VERSION 5.7 ;
  NOWIREEXTENSIONATPIN ON ;
  DIVIDERCHAR "/" ;
  BUSBITCHARS "[]" ;
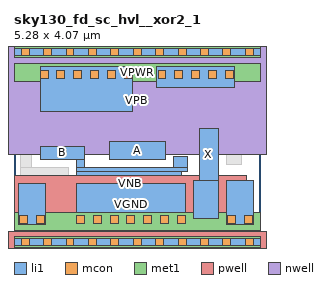
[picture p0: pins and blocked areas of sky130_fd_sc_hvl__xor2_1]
MACRO sky130_fd_sc_hvl__xor2_1
  CLASS BLOCK ;
  FOREIGN sky130_fd_sc_hvl__xor2_1 ;
  ORIGIN 0.000 0.000 ;
  SIZE 5.280 BY 4.070 ;
  PIN A
    ANTENNAGATEAREA 2.250000 ;
    PORT
      LAYER li1 ;
        RECT 2.045 1.775 3.235 2.150 ;
    END
  END A
  PIN B
    ANTENNAGATEAREA 2.250000 ;
    PORT
      LAYER li1 ;
        RECT 0.560 1.775 1.510 2.055 ;
        RECT 1.340 1.595 1.510 1.775 ;
        RECT 3.415 1.595 3.715 1.835 ;
        RECT 1.340 1.505 3.715 1.595 ;
        RECT 1.340 1.425 3.585 1.505 ;
    END
  END B
  PIN VGND
    USE GROUND ;
    PORT
      LAYER li1 ;
        RECT 0.090 0.365 0.680 1.245 ;
        RECT 1.340 0.365 3.670 1.245 ;
        RECT 4.550 0.365 5.140 1.325 ;
      LAYER mcon ;
        RECT 0.120 0.395 0.290 0.565 ;
        RECT 0.480 0.395 0.650 0.565 ;
        RECT 1.340 0.395 1.510 0.565 ;
        RECT 1.700 0.395 1.870 0.565 ;
        RECT 2.060 0.395 2.230 0.565 ;
        RECT 2.420 0.395 2.590 0.565 ;
        RECT 2.780 0.395 2.950 0.565 ;
        RECT 3.140 0.395 3.310 0.565 ;
        RECT 3.500 0.395 3.670 0.565 ;
        RECT 4.580 0.395 4.750 0.565 ;
        RECT 4.940 0.395 5.110 0.565 ;
      LAYER met1 ;
        RECT 0.000 0.255 5.280 0.625 ;
    END
  END VGND
  PIN VNB
    ANTENNADIFFAREA 0.897600 ;
    PORT
      LAYER pwell ;
        RECT 0.020 0.215 4.990 1.415 ;
        RECT -0.130 -0.215 5.410 0.215 ;
      LAYER li1 ;
        RECT 0.000 -0.085 5.280 0.085 ;
      LAYER mcon ;
        RECT 0.155 -0.085 0.325 0.085 ;
        RECT 0.635 -0.085 0.805 0.085 ;
        RECT 1.115 -0.085 1.285 0.085 ;
        RECT 1.595 -0.085 1.765 0.085 ;
        RECT 2.075 -0.085 2.245 0.085 ;
        RECT 2.555 -0.085 2.725 0.085 ;
        RECT 3.035 -0.085 3.205 0.085 ;
        RECT 3.515 -0.085 3.685 0.085 ;
        RECT 3.995 -0.085 4.165 0.085 ;
        RECT 4.475 -0.085 4.645 0.085 ;
        RECT 4.955 -0.085 5.125 0.085 ;
      LAYER met1 ;
        RECT 0.000 -0.115 5.280 0.115 ;
    END
  END VNB
  PIN VPB
    ANTENNADIFFAREA 0.897600 ;
    PORT
      LAYER nwell ;
        RECT -0.330 1.885 5.610 4.485 ;
      LAYER li1 ;
        RECT 0.000 3.985 5.280 4.155 ;
      LAYER mcon ;
        RECT 0.155 3.985 0.325 4.155 ;
        RECT 0.635 3.985 0.805 4.155 ;
        RECT 1.115 3.985 1.285 4.155 ;
        RECT 1.595 3.985 1.765 4.155 ;
        RECT 2.075 3.985 2.245 4.155 ;
        RECT 2.555 3.985 2.725 4.155 ;
        RECT 3.035 3.985 3.205 4.155 ;
        RECT 3.515 3.985 3.685 4.155 ;
        RECT 3.995 3.985 4.165 4.155 ;
        RECT 4.475 3.985 4.645 4.155 ;
        RECT 4.955 3.985 5.125 4.155 ;
      LAYER met1 ;
        RECT 0.000 3.955 5.280 4.185 ;
    END
  END VPB
  PIN VPWR
    USE POWER ;
    PORT
      LAYER li1 ;
        RECT 0.560 2.785 2.530 3.755 ;
        RECT 3.060 3.305 4.720 3.755 ;
      LAYER mcon ;
        RECT 0.560 3.505 0.730 3.675 ;
        RECT 0.920 3.505 1.090 3.675 ;
        RECT 1.280 3.505 1.450 3.675 ;
        RECT 1.640 3.505 1.810 3.675 ;
        RECT 2.000 3.505 2.170 3.675 ;
        RECT 2.360 3.505 2.530 3.675 ;
        RECT 3.085 3.505 3.255 3.675 ;
        RECT 3.445 3.505 3.615 3.675 ;
        RECT 3.805 3.505 3.975 3.675 ;
        RECT 4.165 3.505 4.335 3.675 ;
        RECT 4.525 3.505 4.695 3.675 ;
      LAYER met1 ;
        RECT 0.000 3.445 5.280 3.815 ;
    END
  END VPWR
  PIN X
    ANTENNADIFFAREA 0.637500 ;
    PORT
      LAYER li1 ;
        RECT 3.965 1.325 4.370 2.425 ;
        RECT 3.850 0.495 4.370 1.325 ;
    END
  END X
  OBS
      LAYER li1 ;
        RECT 0.130 2.605 0.380 3.755 ;
        RECT 2.710 3.125 2.880 3.755 ;
        RECT 4.900 3.125 5.150 3.755 ;
        RECT 2.710 2.955 5.150 3.125 ;
        RECT 2.710 2.785 2.880 2.955 ;
        RECT 3.060 2.605 4.720 2.775 ;
        RECT 0.130 2.435 3.230 2.605 ;
        RECT 0.130 1.595 0.380 2.435 ;
        RECT 4.550 1.995 4.720 2.605 ;
        RECT 4.900 2.175 5.150 2.955 ;
        RECT 4.550 1.665 4.880 1.995 ;
        RECT 0.130 1.425 1.160 1.595 ;
        RECT 0.910 0.495 1.160 1.425 ;
  END
END sky130_fd_sc_hvl__xor2_1
END LIBRARY

